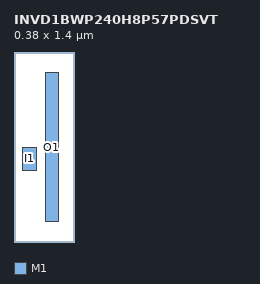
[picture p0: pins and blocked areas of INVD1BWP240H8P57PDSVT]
MACRO INVD1BWP240H8P57PDSVT
  CLASS CORE ;
  SIZE 0.38 BY 1.4 ;
  PIN I1
    DIRECTION INPUT ;
    PORT
      LAYER M1 ;
        RECT 0.06 0.525 0.165 0.7 ;
    END
  END I1
  PIN O1
    DIRECTION OUTPUT ;
    PORT
      LAYER M1 ;
        RECT 0.23 0.15 0.325 1.25 ;
    END
  END O1
END INVD1BWP240H8P57PDSVT
